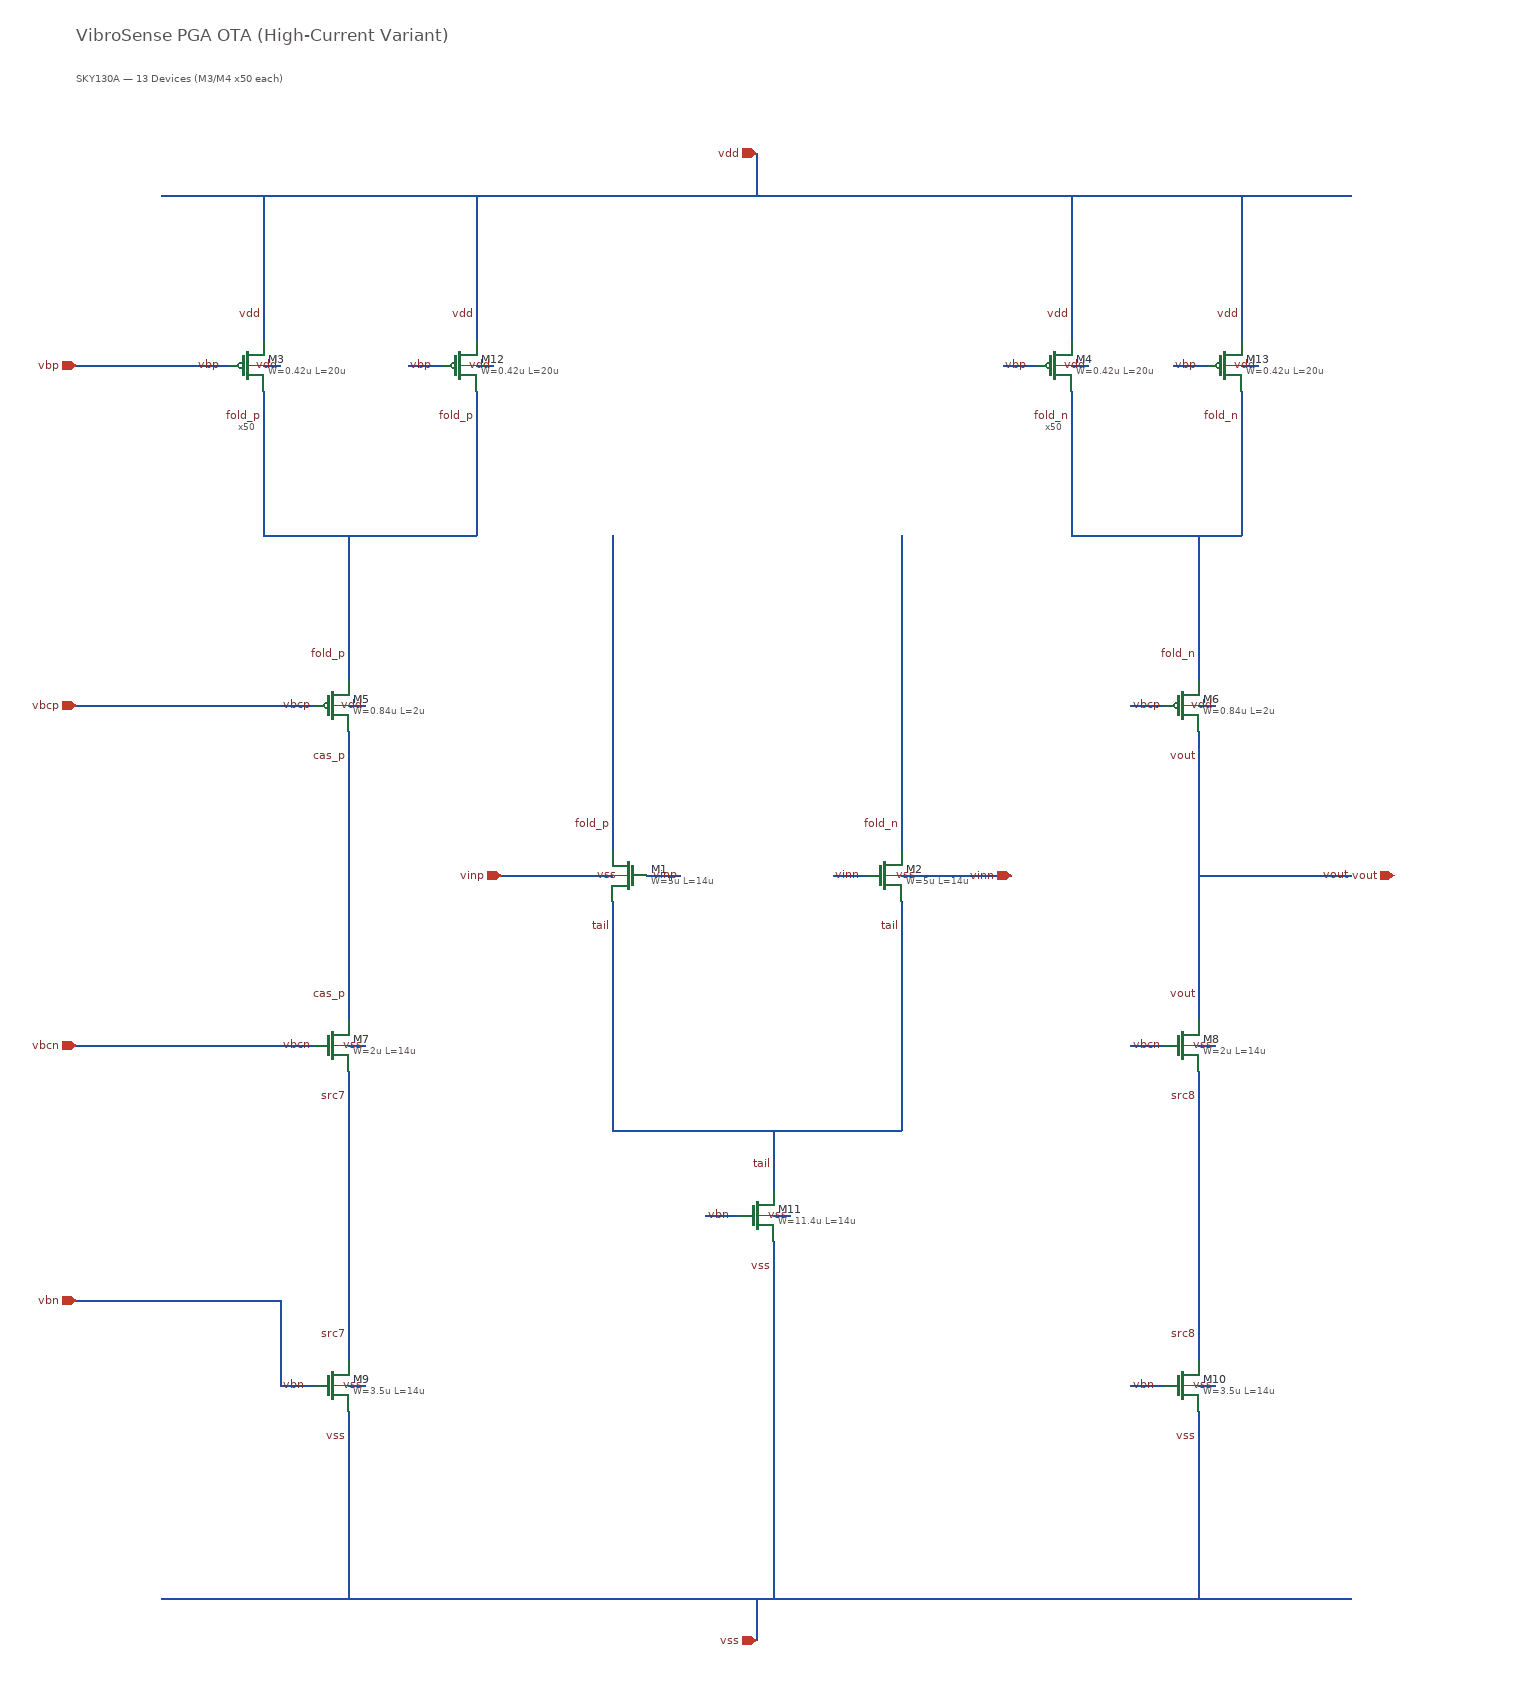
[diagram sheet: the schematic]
v {xschem version=3.4.4 file_version=1.2}
G {}
K {}
V {}
S {}
E {}
N -580 -1370 -580 -1340 {lab=fold_p}
N -620 -1400 -660 -1400 {lab=vbp}
N -580 -1430 -580 -1460 {lab=vdd}
N -580 -1400 -560 -1400 {lab=vdd}
N -330 -1370 -330 -1340 {lab=fold_p}
N -370 -1400 -410 -1400 {lab=vbp}
N -330 -1430 -330 -1460 {lab=vdd}
N -330 -1400 -310 -1400 {lab=vdd}
N 370 -1370 370 -1340 {lab=fold_n}
N 330 -1400 290 -1400 {lab=vbp}
N 370 -1430 370 -1460 {lab=vdd}
N 370 -1400 390 -1400 {lab=vdd}
N 570 -1370 570 -1340 {lab=fold_n}
N 530 -1400 490 -1400 {lab=vbp}
N 570 -1430 570 -1460 {lab=vdd}
N 570 -1400 590 -1400 {lab=vdd}
N -480 -970 -480 -940 {lab=cas_p}
N -520 -1000 -560 -1000 {lab=vbcp}
N -480 -1030 -480 -1060 {lab=fold_p}
N -480 -1000 -460 -1000 {lab=vdd}
N 520 -970 520 -940 {lab=vout}
N 480 -1000 440 -1000 {lab=vbcp}
N 520 -1030 520 -1060 {lab=fold_n}
N 520 -1000 540 -1000 {lab=vdd}
N -480 -630 -480 -660 {lab=cas_p}
N -520 -600 -560 -600 {lab=vbcn}
N -480 -570 -480 -540 {lab=src7}
N -480 -600 -460 -600 {lab=vss}
N 520 -630 520 -660 {lab=vout}
N 480 -600 440 -600 {lab=vbcn}
N 520 -570 520 -540 {lab=src8}
N 520 -600 540 -600 {lab=vss}
N -480 -230 -480 -260 {lab=src7}
N -520 -200 -560 -200 {lab=vbn}
N -480 -170 -480 -140 {lab=vss}
N -480 -200 -460 -200 {lab=vss}
N 520 -230 520 -260 {lab=src8}
N 480 -200 440 -200 {lab=vbn}
N 520 -170 520 -140 {lab=vss}
N 520 -200 540 -200 {lab=vss}
N -170 -830 -170 -860 {lab=fold_p}
N -130 -800 -90 -800 {lab=vinp}
N -170 -770 -170 -740 {lab=tail}
N -170 -800 -190 -800 {lab=vss}
N 170 -830 170 -860 {lab=fold_n}
N 130 -800 90 -800 {lab=vinn}
N 170 -770 170 -740 {lab=tail}
N 170 -800 190 -800 {lab=vss}
N 20 -430 20 -460 {lab=tail}
N -20 -400 -60 -400 {lab=vbn}
N 20 -370 20 -340 {lab=vss}
N 20 -400 40 -400 {lab=vss}
N -580 -1340 -580 -1200 {lab=fold_p}
N -330 -1340 -330 -1200 {lab=fold_p}
N -580 -1200 -330 -1200 {lab=fold_p}
N -480 -1200 -480 -1060 {lab=fold_p}
N 370 -1340 370 -1200 {lab=fold_n}
N 570 -1340 570 -1200 {lab=fold_n}
N 370 -1200 570 -1200 {lab=fold_n}
N 520 -1200 520 -1060 {lab=fold_n}
N -480 -940 -480 -660 {lab=cas_p}
N 520 -940 520 -660 {lab=vout}
N -480 -540 -480 -260 {lab=src7}
N 520 -540 520 -260 {lab=src8}
N -170 -740 -170 -500 {lab=tail}
N 170 -740 170 -500 {lab=tail}
N -170 -500 170 -500 {lab=tail}
N 20 -500 20 -460 {lab=tail}
N -170 -860 -170 -1200 {lab=fold_p}
N 170 -860 170 -1200 {lab=fold_n}
N -700 -1600 700 -1600 {lab=vdd}
N -580 -1460 -580 -1600 {lab=vdd}
N -330 -1460 -330 -1600 {lab=vdd}
N 370 -1460 370 -1600 {lab=vdd}
N 570 -1460 570 -1600 {lab=vdd}
N -700 50 700 50 {lab=vss}
N -480 -140 -480 50 {lab=vss}
N 520 -140 520 50 {lab=vss}
N 20 -340 20 50 {lab=vss}
N 520 -800 700 -800 {lab=vout}
N 0 -1650 0 -1600 {lab=vdd}
N 0 100 0 50 {lab=vss}
N -300 -800 -190 -800 {lab=vinp}
N 300 -800 190 -800 {lab=vinn}
N -800 -300 -560 -300 {lab=vbn}
N -560 -300 -560 -200 {lab=vbn}
N -800 -600 -540 -600 {lab=vbcn}
N -800 -1400 -660 -1400 {lab=vbp}
N -800 -1000 -560 -1000 {lab=vbcp}
T {VibroSense PGA OTA (High-Current Variant)} -800 -1800 0 0 0.6 0.6 {}
T {SKY130A — 13 Devices (M3/M4 x50 each)} -800 -1750 0 0 0.35 0.35 {layer=8}
T {x50} -610 -1340 0 0 0.3 0.3 {layer=5}
T {x50} 340 -1340 0 0 0.3 0.3 {layer=5}
C {/home/ubuntu/pdk/volare/sky130/versions/6d4d11780c40b20ee63cc98e645307a9bf2b2ab8/sky130A/libs.tech/xschem/sky130_fd_pr/pfet_01v8.sym} -600 -1400 0 0 {name=M3 L=20u W=0.42u nf=1 mult=50 model=pfet_01v8 spiceprefix=X}
C {devices/lab_pin.sym} -580 -1340 3 0 {name=p1 lab=fold_p}
C {devices/lab_pin.sym} -660 -1400 0 1 {name=p2 lab=vbp}
C {devices/lab_pin.sym} -580 -1460 1 0 {name=p3 lab=vdd}
C {devices/lab_pin.sym} -560 -1400 0 0 {name=p4 lab=vdd}
C {/home/ubuntu/pdk/volare/sky130/versions/6d4d11780c40b20ee63cc98e645307a9bf2b2ab8/sky130A/libs.tech/xschem/sky130_fd_pr/pfet_01v8.sym} -350 -1400 0 0 {name=M12 L=20u W=0.42u nf=1 mult=1 model=pfet_01v8 spiceprefix=X}
C {devices/lab_pin.sym} -330 -1340 3 0 {name=p5 lab=fold_p}
C {devices/lab_pin.sym} -410 -1400 0 1 {name=p6 lab=vbp}
C {devices/lab_pin.sym} -330 -1460 1 0 {name=p7 lab=vdd}
C {devices/lab_pin.sym} -310 -1400 0 0 {name=p8 lab=vdd}
C {/home/ubuntu/pdk/volare/sky130/versions/6d4d11780c40b20ee63cc98e645307a9bf2b2ab8/sky130A/libs.tech/xschem/sky130_fd_pr/pfet_01v8.sym} 350 -1400 0 0 {name=M4 L=20u W=0.42u nf=1 mult=50 model=pfet_01v8 spiceprefix=X}
C {devices/lab_pin.sym} 370 -1340 3 0 {name=p9 lab=fold_n}
C {devices/lab_pin.sym} 290 -1400 0 1 {name=p10 lab=vbp}
C {devices/lab_pin.sym} 370 -1460 1 0 {name=p11 lab=vdd}
C {devices/lab_pin.sym} 390 -1400 0 0 {name=p12 lab=vdd}
C {/home/ubuntu/pdk/volare/sky130/versions/6d4d11780c40b20ee63cc98e645307a9bf2b2ab8/sky130A/libs.tech/xschem/sky130_fd_pr/pfet_01v8.sym} 550 -1400 0 0 {name=M13 L=20u W=0.42u nf=1 mult=1 model=pfet_01v8 spiceprefix=X}
C {devices/lab_pin.sym} 570 -1340 3 0 {name=p13 lab=fold_n}
C {devices/lab_pin.sym} 490 -1400 0 1 {name=p14 lab=vbp}
C {devices/lab_pin.sym} 570 -1460 1 0 {name=p15 lab=vdd}
C {devices/lab_pin.sym} 590 -1400 0 0 {name=p16 lab=vdd}
C {/home/ubuntu/pdk/volare/sky130/versions/6d4d11780c40b20ee63cc98e645307a9bf2b2ab8/sky130A/libs.tech/xschem/sky130_fd_pr/pfet_01v8.sym} -500 -1000 0 0 {name=M5 L=2u W=0.84u nf=1 mult=1 model=pfet_01v8 spiceprefix=X}
C {devices/lab_pin.sym} -480 -940 3 0 {name=p17 lab=cas_p}
C {devices/lab_pin.sym} -560 -1000 0 1 {name=p18 lab=vbcp}
C {devices/lab_pin.sym} -480 -1060 1 0 {name=p19 lab=fold_p}
C {devices/lab_pin.sym} -460 -1000 0 0 {name=p20 lab=vdd}
C {/home/ubuntu/pdk/volare/sky130/versions/6d4d11780c40b20ee63cc98e645307a9bf2b2ab8/sky130A/libs.tech/xschem/sky130_fd_pr/pfet_01v8.sym} 500 -1000 0 0 {name=M6 L=2u W=0.84u nf=1 mult=1 model=pfet_01v8 spiceprefix=X}
C {devices/lab_pin.sym} 520 -940 3 0 {name=p21 lab=vout}
C {devices/lab_pin.sym} 440 -1000 0 1 {name=p22 lab=vbcp}
C {devices/lab_pin.sym} 520 -1060 1 0 {name=p23 lab=fold_n}
C {devices/lab_pin.sym} 540 -1000 0 0 {name=p24 lab=vdd}
C {/home/ubuntu/pdk/volare/sky130/versions/6d4d11780c40b20ee63cc98e645307a9bf2b2ab8/sky130A/libs.tech/xschem/sky130_fd_pr/nfet_01v8.sym} -500 -600 0 0 {name=M7 L=14u W=2u nf=1 mult=1 model=nfet_01v8 spiceprefix=X}
C {devices/lab_pin.sym} -480 -660 1 0 {name=p25 lab=cas_p}
C {devices/lab_pin.sym} -560 -600 0 1 {name=p26 lab=vbcn}
C {devices/lab_pin.sym} -480 -540 3 0 {name=p27 lab=src7}
C {devices/lab_pin.sym} -460 -600 0 0 {name=p28 lab=vss}
C {/home/ubuntu/pdk/volare/sky130/versions/6d4d11780c40b20ee63cc98e645307a9bf2b2ab8/sky130A/libs.tech/xschem/sky130_fd_pr/nfet_01v8.sym} 500 -600 0 0 {name=M8 L=14u W=2u nf=1 mult=1 model=nfet_01v8 spiceprefix=X}
C {devices/lab_pin.sym} 520 -660 1 0 {name=p29 lab=vout}
C {devices/lab_pin.sym} 440 -600 0 1 {name=p30 lab=vbcn}
C {devices/lab_pin.sym} 520 -540 3 0 {name=p31 lab=src8}
C {devices/lab_pin.sym} 540 -600 0 0 {name=p32 lab=vss}
C {/home/ubuntu/pdk/volare/sky130/versions/6d4d11780c40b20ee63cc98e645307a9bf2b2ab8/sky130A/libs.tech/xschem/sky130_fd_pr/nfet_01v8.sym} -500 -200 0 0 {name=M9 L=14u W=3.5u nf=1 mult=1 model=nfet_01v8 spiceprefix=X}
C {devices/lab_pin.sym} -480 -260 1 0 {name=p33 lab=src7}
C {devices/lab_pin.sym} -560 -200 0 1 {name=p34 lab=vbn}
C {devices/lab_pin.sym} -480 -140 3 0 {name=p35 lab=vss}
C {devices/lab_pin.sym} -460 -200 0 0 {name=p36 lab=vss}
C {/home/ubuntu/pdk/volare/sky130/versions/6d4d11780c40b20ee63cc98e645307a9bf2b2ab8/sky130A/libs.tech/xschem/sky130_fd_pr/nfet_01v8.sym} 500 -200 0 0 {name=M10 L=14u W=3.5u nf=1 mult=1 model=nfet_01v8 spiceprefix=X}
C {devices/lab_pin.sym} 520 -260 1 0 {name=p37 lab=src8}
C {devices/lab_pin.sym} 440 -200 0 1 {name=p38 lab=vbn}
C {devices/lab_pin.sym} 520 -140 3 0 {name=p39 lab=vss}
C {devices/lab_pin.sym} 540 -200 0 0 {name=p40 lab=vss}
C {/home/ubuntu/pdk/volare/sky130/versions/6d4d11780c40b20ee63cc98e645307a9bf2b2ab8/sky130A/libs.tech/xschem/sky130_fd_pr/nfet_01v8.sym} -150 -800 0 1 {name=M1 L=14u W=5u nf=1 mult=1 model=nfet_01v8 spiceprefix=X}
C {devices/lab_pin.sym} -170 -860 1 0 {name=p41 lab=fold_p}
C {devices/lab_pin.sym} -90 -800 0 0 {name=p42 lab=vinp}
C {devices/lab_pin.sym} -170 -740 3 0 {name=p43 lab=tail}
C {devices/lab_pin.sym} -190 -800 0 1 {name=p44 lab=vss}
C {/home/ubuntu/pdk/volare/sky130/versions/6d4d11780c40b20ee63cc98e645307a9bf2b2ab8/sky130A/libs.tech/xschem/sky130_fd_pr/nfet_01v8.sym} 150 -800 0 0 {name=M2 L=14u W=5u nf=1 mult=1 model=nfet_01v8 spiceprefix=X}
C {devices/lab_pin.sym} 170 -860 1 0 {name=p45 lab=fold_n}
C {devices/lab_pin.sym} 90 -800 0 1 {name=p46 lab=vinn}
C {devices/lab_pin.sym} 170 -740 3 0 {name=p47 lab=tail}
C {devices/lab_pin.sym} 190 -800 0 0 {name=p48 lab=vss}
C {/home/ubuntu/pdk/volare/sky130/versions/6d4d11780c40b20ee63cc98e645307a9bf2b2ab8/sky130A/libs.tech/xschem/sky130_fd_pr/nfet_01v8.sym} 0 -400 0 0 {name=M11 L=14u W=11.4u nf=1 mult=1 model=nfet_01v8 spiceprefix=X}
C {devices/lab_pin.sym} 20 -460 1 0 {name=p49 lab=tail}
C {devices/lab_pin.sym} -60 -400 0 1 {name=p50 lab=vbn}
C {devices/lab_pin.sym} 20 -340 3 0 {name=p51 lab=vss}
C {devices/lab_pin.sym} 40 -400 0 0 {name=p52 lab=vss}
C {devices/lab_pin.sym} 700 -800 0 0 {name=p53 lab=vout}
C {devices/iopin.sym} -300 -800 2 0 {name=p54 lab=vinp}
C {devices/iopin.sym} 300 -800 2 0 {name=p55 lab=vinn}
C {devices/iopin.sym} 750 -800 0 0 {name=p56 lab=vout}
C {devices/iopin.sym} 0 -1650 3 0 {name=p57 lab=vdd}
C {devices/iopin.sym} 0 100 1 0 {name=p58 lab=vss}
C {devices/iopin.sym} -800 -300 2 0 {name=p59 lab=vbn}
C {devices/iopin.sym} -800 -600 2 0 {name=p60 lab=vbcn}
C {devices/iopin.sym} -800 -1400 2 0 {name=p61 lab=vbp}
C {devices/iopin.sym} -800 -1000 2 0 {name=p62 lab=vbcp}
